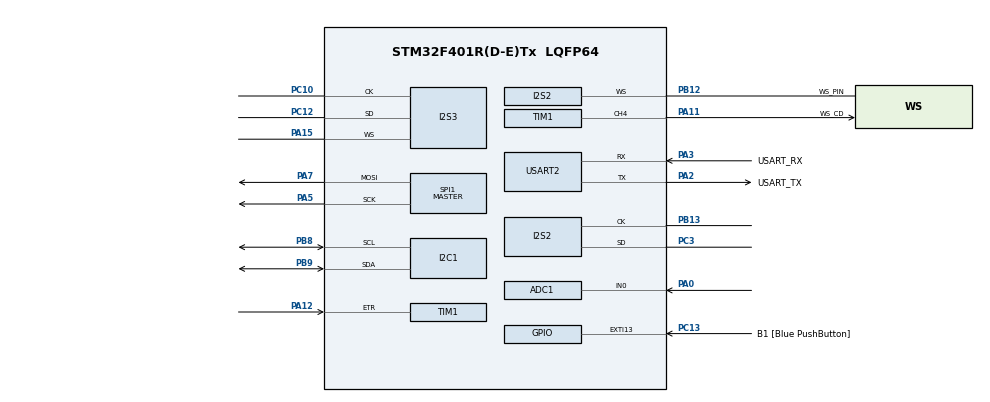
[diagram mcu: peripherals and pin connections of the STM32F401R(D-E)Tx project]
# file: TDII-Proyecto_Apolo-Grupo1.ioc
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ADC1.Channel-0\#ChannelRegularConversion=ADC_CHANNEL_0
ADC1.NbrOfConversionFlag=1
ADC1.Rank-0\#ChannelRegularConversion=1
ADC1.Resolution=ADC_RESOLUTION_10B
ADC1.SamplingTime-0\#ChannelRegularConversion=ADC_SAMPLETIME_3CYCLES
ADC1.master=1
Dma.Request0=SPI3_TX
Dma.Request1=SPI2_RX
Dma.Request2=SPI1_TX
Dma.SPI1_TX.2.Direction=DMA_MEMORY_TO_PERIPH
Dma.SPI1_TX.2.FIFOMode=DMA_FIFOMODE_DISABLE
Dma.SPI1_TX.2.Instance=DMA2_Stream3
Dma.SPI1_TX.2.MemDataAlignment=DMA_MDATAALIGN_BYTE
Dma.SPI1_TX.2.MemInc=DMA_MINC_ENABLE
Dma.SPI1_TX.2.Mode=DMA_CIRCULAR
Dma.SPI1_TX.2.PeriphDataAlignment=DMA_PDATAALIGN_BYTE
Dma.SPI1_TX.2.PeriphInc=DMA_PINC_DISABLE
Dma.SPI1_TX.2.Priority=DMA_PRIORITY_VERY_HIGH
Dma.SPI2_RX.1.Direction=DMA_PERIPH_TO_MEMORY
Dma.SPI2_RX.1.FIFOMode=DMA_FIFOMODE_DISABLE
Dma.SPI2_RX.1.Instance=DMA1_Stream3
Dma.SPI2_RX.1.MemDataAlignment=DMA_MDATAALIGN_HALFWORD
Dma.SPI2_RX.1.MemInc=DMA_MINC_ENABLE
Dma.SPI2_RX.1.Mode=DMA_CIRCULAR
Dma.SPI2_RX.1.PeriphDataAlignment=DMA_PDATAALIGN_HALFWORD
Dma.SPI2_RX.1.PeriphInc=DMA_PINC_DISABLE
Dma.SPI2_RX.1.Priority=DMA_PRIORITY_VERY_HIGH
Dma.SPI3_TX.0.Direction=DMA_MEMORY_TO_PERIPH
Dma.SPI3_TX.0.FIFOMode=DMA_FIFOMODE_DISABLE
Dma.SPI3_TX.0.Instance=DMA1_Stream5
Dma.SPI3_TX.0.MemDataAlignment=DMA_MDATAALIGN_HALFWORD
Dma.SPI3_TX.0.MemInc=DMA_MINC_ENABLE
Dma.SPI3_TX.0.Mode=DMA_CIRCULAR
Dma.SPI3_TX.0.PeriphDataAlignment=DMA_PDATAALIGN_HALFWORD
Dma.SPI3_TX.0.PeriphInc=DMA_PINC_DISABLE
Dma.SPI3_TX.0.Priority=DMA_PRIORITY_VERY_HIGH
FREERTOS.Tasks01=defaultTask,0,128,StartDefaultTask,Default,NULL,Dynamic,NULL,NULL
FREERTOS.configENABLE_FPU=1
FREERTOS.configTOTAL_HEAP_SIZE=30000
FREERTOS.configUSE_NEWLIB_REENTRANT=1
I2S2.AudioFreq=AudioFreqCustomValue
I2S2.AudioFreqCustom=44100
I2S2.CPOL=I2S_CPOL_HIGH
I2S2.ErrorAudioFreq=0.26 %
I2S2.FullDuplexMode=I2S_FULLDUPLEXMODE_DISABLE
I2S2.Instance=SPI$Index
I2S2.Mode=I2S_MODE_SLAVE_RX
I2S2.RealAudioFreq=44.117 KHz
I2S2.VirtualMode=I2S_MODE_SLAVE
I2S3.AudioFreq=AudioFreqCustomValue
I2S3.AudioFreqCustom=44100
I2S3.CPOL=I2S_CPOL_HIGH
I2S3.ErrorAudioFreq=0.26 %
I2S3.FullDuplexMode=I2S_FULLDUPLEXMODE_DISABLE
I2S3.Instance=SPI$Index
I2S3.RealAudioFreq=44.117 KHz
I2S3.VirtualMode=I2S_MODE_MASTER
Mcu.Family=STM32F4
Mcu.Name=STM32F401R(D-E)Tx
Mcu.Package=LQFP64
NVIC.DMA1_Stream3_IRQn=true\:5\:0\:false\:false\:true\:true\:false\:true\:true
NVIC.DMA1_Stream5_IRQn=true\:5\:0\:false\:false\:true\:true\:false\:true\:true
NVIC.DMA2_Stream3_IRQn=true\:5\:0\:false\:false\:true\:true\:false\:true\:true
NVIC.PriorityGroup=NVIC_PRIORITYGROUP_4
NVIC.TIM3_IRQn=true\:15\:0\:false\:false\:true\:false\:false\:true\:true
NVIC.TimeBase=TIM3_IRQn
NVIC.TimeBaseIP=TIM3
PA0-WKUP.Signal=ADCx_IN0
PA11.GPIO_Label=WS_CD
PA11.GPIO_Speed=GPIO_SPEED_FREQ_VERY_HIGH
PA11.Signal=S_TIM1_CH4
PA12.Signal=S_TIM1_ETR
PA13.GPIO_Label=TMS
PA13.Mode=Serial_Wire
PA13.Signal=SYS_JTMS-SWDIO
PA14.GPIO_Label=TCK
PA14.Mode=Serial_Wire
PA14.Signal=SYS_JTCK-SWCLK
PA15.GPIO_Speed=GPIO_SPEED_FREQ_HIGH
PA15.Mode=Half_Duplex_Master
PA15.Signal=I2S3_WS
PA2.GPIO_Label=USART_TX
PA2.GPIO_Mode=GPIO_MODE_AF_PP
PA2.GPIO_PuPd=GPIO_NOPULL
PA2.GPIO_Speed=GPIO_SPEED_FREQ_LOW
PA2.Mode=Asynchronous
PA2.Signal=USART2_TX
PA3.GPIO_Label=USART_RX
PA3.GPIO_Mode=GPIO_MODE_AF_PP
PA3.GPIO_PuPd=GPIO_NOPULL
PA3.GPIO_Speed=GPIO_SPEED_FREQ_LOW
PA3.Mode=Asynchronous
PA3.Signal=USART2_RX
PA5.Mode=TX_Only_Simplex_Unidirect_Master
PA5.Signal=SPI1_SCK
PA7.Mode=TX_Only_Simplex_Unidirect_Master
PA7.Signal=SPI1_MOSI
PB12.GPIO_Label=WS_PIN
PB12.GPIO_Speed=GPIO_SPEED_FREQ_HIGH
PB12.Mode=Half_Duplex_Slave
PB12.Signal=I2S2_WS
PB13.GPIO_Speed=GPIO_SPEED_FREQ_HIGH
PB13.Mode=Half_Duplex_Slave
PB13.Signal=I2S2_CK
PB8.GPIO_Pu=GPIO_PULLUP
PB8.Mode=I2C
PB8.Signal=I2C1_SCL
PB9.GPIO_Pu=GPIO_PULLUP
PB9.Mode=I2C
PB9.Signal=I2C1_SDA
PC10.GPIO_Speed=GPIO_SPEED_FREQ_HIGH
PC10.Mode=Half_Duplex_Master
PC10.Signal=I2S3_CK
PC12.GPIO_Speed=GPIO_SPEED_FREQ_HIGH
PC12.Mode=Half_Duplex_Master
PC12.Signal=I2S3_SD
PC13-ANTI_TAMP.GPIO_Label=B1 [Blue PushButton]
PC13-ANTI_TAMP.GPIO_ModeDefaultEXTI=GPIO_MODE_IT_FALLING
PC13-ANTI_TAMP.GPIO_PuPd=GPIO_NOPULL
PC13-ANTI_TAMP.Signal=GPXTI13
PC14-OSC32_IN.Mode=LSE-External-Oscillator
PC14-OSC32_IN.Signal=RCC_OSC32_IN
PC15-OSC32_OUT.Mode=LSE-External-Oscillator
PC15-OSC32_OUT.Signal=RCC_OSC32_OUT
PC3.GPIO_Speed=GPIO_SPEED_FREQ_HIGH
PC3.Mode=Half_Duplex_Slave
PC3.Signal=I2S2_SD
PH0\ -\ OSC_IN.Mode=HSE-External-Clock-Source
PH0\ -\ OSC_IN.Signal=RCC_OSC_IN
PH1\ -\ OSC_OUT.Mode=HSE-External-Clock-Source
PH1\ -\ OSC_OUT.Signal=RCC_OSC_OUT
ProjectManager.HeapSize=0x200
ProjectManager.StackSize=0x400
ProjectManager.TargetToolchain=STM32CubeIDE
RCC.48MHZClocksFreq_Value=19428571.42857143
RCC.AHBFreq_Value=68000000
RCC.APB1CLKDivider=RCC_HCLK_DIV2
RCC.APB1Freq_Value=34000000
RCC.APB1TimFreq_Value=68000000
RCC.APB2Freq_Value=68000000
RCC.APB2TimFreq_Value=68000000
RCC.CortexFreq_Value=68000000
RCC.HCLKFreq_Value=68000000
RCC.HSE_VALUE=8000000
RCC.HSI_VALUE=16000000
RCC.PLLI2SN=72
RCC.PLLI2SR=3
RCC.PLLM=4
RCC.PLLN=68
RCC.PLLQ=7
RCC.PLLSourceVirtual=RCC_PLLSOURCE_HSE
RCC.SYSCLKFreq_VALUE=68000000
RCC.SYSCLKSource=RCC_SYSCLKSOURCE_PLLCLK
RCC.VCOOutputFreq_Value=136000000
SH.ADCx_IN0.0=ADC1_IN0,IN0
SH.S_TIM1_CH4.0=TIM1_CH4,Output Compare4 CH4
SH.S_TIM1_ETR.0=TIM1_ETR,ClockSourceETR_Mode2
SPI1.BaudRatePrescaler=SPI_BAUDRATEPRESCALER_32
SPI1.DataSize=SPI_DATASIZE_8BIT
SPI1.Direction=SPI_DIRECTION_2LINES
SPI1.Mode=SPI_MODE_MASTER
SPI1.VirtualType=VM_MASTER
STMicroelectronics.X-CUBE-TOUCHGFX.4.22.0.ApplicationCcGraphicsJjApplication=TouchGFXOoGenerator
STMicroelectronics.X-CUBE-TOUCHGFX.4.22.0.tgfx_buffering_strategy=Partial
STMicroelectronics.X-CUBE-TOUCHGFX.4.22.0.tgfx_custom_height=320
STMicroelectronics.X-CUBE-TOUCHGFX.4.22.0.tgfx_custom_width=480
STMicroelectronics.X-CUBE-TOUCHGFX.4.22.0_IsPackSelfContextualization=true
TIM1.Channel-Output\ Compare4\ CH4=TIM_CHANNEL_4
TIM1.OC4Preload=DISABLE
TIM1.OCMode_4=TIM_OCMODE_TOGGLE
TIM1.Period=23
TIM1.Pulse-Output\ Compare4\ CH4=0
TIM2.Prescaler=0
USART2.VirtualMode=VM_ASYNC
VP_CRC_VS_CRC.Mode=CRC_Activate
VP_FREERTOS_VS_CMSIS_V1.Mode=CMSIS_V1
VP_STMicroelectronics.X-CUBE-TOUCHGFX_VS_GraphicsJjApplication_4.22.0.Mode=GraphicsJjApplication
VP_SYS_VS_tim3.Mode=TIM3
VP_TIM2_VS_ClockSourceINT.Mode=Internal
board=NUCLEO-F401RE

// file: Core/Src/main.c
/* USER CODE BEGIN Header */
/**
  ******************************************************************************
  * @file           : main.c
  * @brief          : Main program body
  ******************************************************************************
  * @attention
  *
  * Copyright (c) 2023 STMicroelectronics.
  * All rights reserved.
  *
  * This software is licensed under terms that can be found in the LICENSE file
  * in the root directory of this software component.
  * If no LICENSE file comes with this software, it is provided AS-IS.
  *
  ******************************************************************************
  */
/* USER CODE END Header */
#include "main.h"
#include "cmsis_os.h"
#include "app_touchgfx.h"

/* USER CODE BEGIN PTD */
#include "Driver_I2S.h"
#include "process.h"
/* USER CODE END PTD */

ADC_HandleTypeDef hadc1;

CRC_HandleTypeDef hcrc;

I2C_HandleTypeDef hi2c1;

I2S_HandleTypeDef hi2s2;
I2S_HandleTypeDef hi2s3;
DMA_HandleTypeDef hdma_spi2_rx;
DMA_HandleTypeDef hdma_spi3_tx;

SPI_HandleTypeDef hspi1;
DMA_HandleTypeDef hdma_spi1_tx;

TIM_HandleTypeDef htim1;
TIM_HandleTypeDef htim2;

UART_HandleTypeDef huart2;

osThreadId defaultTaskHandle;
/* USER CODE BEGIN PV */
SemaphoreHandle_t semSaveData;
SemaphoreHandle_t semProcessData; // semaforo para indicar si se puede tocar o no el buffer de entrada/salida
SemaphoreHandle_t semCalcCoefs;
SemaphoreHandle_t semI2CResource;
SemaphoreHandle_t semCalcVolume;
SemaphoreHandle_t semDataReady;

/* USER CODE END PV */

void SystemClock_Config(void);
void PeriphCommonClock_Config(void);
static void MX_GPIO_Init(void);
static void MX_DMA_Init(void);
static void MX_USART2_UART_Init(void);
static void MX_ADC1_Init(void);
static void MX_CRC_Init(void);
static void MX_TIM2_Init(void);
static void MX_I2C1_Init(void);
static void MX_I2S3_Init(void);
static void MX_TIM1_Init(void);
static void MX_I2S2_Init(void);
static void MX_SPI1_Init(void);
void StartDefaultTask(void const * argument);

/* USER CODE BEGIN 0 */

/*
uint32_t tim1_cuenta=0;
extern TIM_HandleTypeDef htim2;
extern uint32_t tim1_cuenta;
tim1_cuenta = 0 ;
__HAL_TIM_SET_COUNTER(&htim2,0);
tim1_cuenta = __HAL_TIM_GET_COUNTER(&htim2);
*/

//I2S 2
void HAL_I2S_RxCpltCallback(I2S_HandleTypeDef *hi2s) {
	callbackI2SRx_CMP();
}
void HAL_I2S_RxHalfCpltCallback(I2S_HandleTypeDef *hi2s) {
	callbackI2SRx_HALF();
}

//I2S 3
void HAL_I2S_TxCpltCallback(I2S_HandleTypeDef *hi2s) {
	callbackI2STx_CMP();
}
void HAL_I2S_TxHalfCpltCallback(I2S_HandleTypeDef *hi2s) {
	callbackI2STx_HALF();
}
void HAL_SPI_TxCpltCallback(SPI_HandleTypeDef *hspi) {
	callbackSPITx_CMP();
}
void HAL_SPI_TxHalfCallback(SPI_HandleTypeDef *hspi) {
	callbackSPITx_HALF();
}

void HAL_TIM_TriggerCallback(TIM_HandleTypeDef *htim){

}
/* USER CODE END 0 */

int main(void)
{

  /* MCU Configuration--------------------------------------------------------*/

  /* Reset of all peripherals, Initializes the Flash interface and the Systick. */
  HAL_Init();

  /* Configure the system clock */
  SystemClock_Config();

/* Configure the peripherals common clocks */
  PeriphCommonClock_Config();

  /* Initialize all configured peripherals */
  MX_GPIO_Init();
  MX_DMA_Init();
  MX_USART2_UART_Init();
  MX_ADC1_Init();
  MX_CRC_Init();
  MX_TIM2_Init();
  MX_I2C1_Init();
  MX_I2S3_Init();
  MX_TIM1_Init();
  MX_I2S2_Init();
  MX_SPI1_Init();
  MX_TouchGFX_Init();
  /* Call PreOsInit function */
  MX_TouchGFX_PreOSInit();
  /* USER CODE BEGIN 2 */
  HAL_TIM_Base_Start(&htim2); // lo uso para medir tiempos

  /* USER CODE END 2 */

  /* USER CODE BEGIN RTOS_SEMAPHORES */
  /* add semaphores, ... */
  init_semaphores();

  /* USER CODE END RTOS_SEMAPHORES */

  /* USER CODE BEGIN RTOS_QUEUES */
  /* add queues, ... */
#if 0
  /* USER CODE END RTOS_QUEUES */

  /* Create the thread(s) */
  /* definition and creation of defaultTask */
  osThreadDef(defaultTask, StartDefaultTask, osPriorityNormal, 0, 128);
  defaultTaskHandle = osThreadCreate(osThread(defaultTask), NULL);

  /* USER CODE BEGIN RTOS_THREADS */
#endif

  init_tasks();

  /* add threads, ... */
  vTaskStartScheduler();
  /* USER CODE END RTOS_THREADS */

  /* Start scheduler */
  osKernelStart();

  /* We should never get here as control is now taken by the scheduler */
  /* Infinite loop */
  while (1)
  {

  }
}

void SystemClock_Config(void)
{
  RCC_OscInitTypeDef RCC_OscInitStruct = {0};
  RCC_ClkInitTypeDef RCC_ClkInitStruct = {0};

  /** Configure the main internal regulator output voltage
  */
  __HAL_RCC_PWR_CLK_ENABLE();
  __HAL_PWR_VOLTAGESCALING_CONFIG(PWR_REGULATOR_VOLTAGE_SCALE2);

  /** Initializes the RCC Oscillators according to the specified parameters
  * in the RCC_OscInitTypeDef structure.
  */
  RCC_OscInitStruct.OscillatorType = RCC_OSCILLATORTYPE_HSE;
  RCC_OscInitStruct.HSEState = RCC_HSE_BYPASS;
  RCC_OscInitStruct.PLL.PLLState = RCC_PLL_ON;
  RCC_OscInitStruct.PLL.PLLSource = RCC_PLLSOURCE_HSE;
  RCC_OscInitStruct.PLL.PLLM = 4;
  RCC_OscInitStruct.PLL.PLLN = 84;
  RCC_OscInitStruct.PLL.PLLP = RCC_PLLP_DIV2;
  RCC_OscInitStruct.PLL.PLLQ = 7;
  if (HAL_RCC_OscConfig(&RCC_OscInitStruct) != HAL_OK)
  {
    Error_Handler();
  }

  /** Initializes the CPU, AHB and APB buses clocks
  */
  RCC_ClkInitStruct.ClockType = RCC_CLOCKTYPE_HCLK|RCC_CLOCKTYPE_SYSCLK
                              |RCC_CLOCKTYPE_PCLK1|RCC_CLOCKTYPE_PCLK2;
  RCC_ClkInitStruct.SYSCLKSource = RCC_SYSCLKSOURCE_PLLCLK;
  RCC_ClkInitStruct.AHBCLKDivider = RCC_SYSCLK_DIV1;
  RCC_ClkInitStruct.APB1CLKDivider = RCC_HCLK_DIV2;
  RCC_ClkInitStruct.APB2CLKDivider = RCC_HCLK_DIV1;

  if (HAL_RCC_ClockConfig(&RCC_ClkInitStruct, FLASH_LATENCY_2) != HAL_OK)
  {
    Error_Handler();
  }
}

void PeriphCommonClock_Config(void)
{
  RCC_PeriphCLKInitTypeDef PeriphClkInitStruct = {0};

  /** Initializes the peripherals clock
  */
  PeriphClkInitStruct.PeriphClockSelection = RCC_PERIPHCLK_I2S;
  PeriphClkInitStruct.PLLI2S.PLLI2SN = 72;
  PeriphClkInitStruct.PLLI2S.PLLI2SR = 3;
  if (HAL_RCCEx_PeriphCLKConfig(&PeriphClkInitStruct) != HAL_OK)
  {
    Error_Handler();
  }
}

static void MX_ADC1_Init(void)
{

  ADC_ChannelConfTypeDef sConfig = {0};

  /** Configure the global features of the ADC (Clock, Resolution, Data Alignment and number of conversion)
  */
  hadc1.Instance = ADC1;
  hadc1.Init.ClockPrescaler = ADC_CLOCK_SYNC_PCLK_DIV4;
  hadc1.Init.Resolution = ADC_RESOLUTION_10B;
  hadc1.Init.ScanConvMode = DISABLE;
  hadc1.Init.ContinuousConvMode = DISABLE;
  hadc1.Init.DiscontinuousConvMode = DISABLE;
  hadc1.Init.ExternalTrigConvEdge = ADC_EXTERNALTRIGCONVEDGE_NONE;
  hadc1.Init.ExternalTrigConv = ADC_SOFTWARE_START;
  hadc1.Init.DataAlign = ADC_DATAALIGN_RIGHT;
  hadc1.Init.NbrOfConversion = 1;
  hadc1.Init.DMAContinuousRequests = DISABLE;
  hadc1.Init.EOCSelection = ADC_EOC_SINGLE_CONV;
  if (HAL_ADC_Init(&hadc1) != HAL_OK)
  {
    Error_Handler();
  }

  /** Configure for the selected ADC regular channel its corresponding rank in the sequencer and its sample time.
  */
  sConfig.Channel = ADC_CHANNEL_0;
  sConfig.Rank = 1;
  sConfig.SamplingTime = ADC_SAMPLETIME_3CYCLES;
  if (HAL_ADC_ConfigChannel(&hadc1, &sConfig) != HAL_OK)
  {
    Error_Handler();
  }

}

static void MX_CRC_Init(void)
{

  hcrc.Instance = CRC;
  if (HAL_CRC_Init(&hcrc) != HAL_OK)
  {
    Error_Handler();
  }

}

static void MX_I2C1_Init(void)
{

  hi2c1.Instance = I2C1;
  hi2c1.Init.ClockSpeed = 100000;
  hi2c1.Init.DutyCycle = I2C_DUTYCYCLE_2;
  hi2c1.Init.OwnAddress1 = 0;
  hi2c1.Init.AddressingMode = I2C_ADDRESSINGMODE_7BIT;
  hi2c1.Init.DualAddressMode = I2C_DUALADDRESS_DISABLE;
  hi2c1.Init.OwnAddress2 = 0;
  hi2c1.Init.GeneralCallMode = I2C_GENERALCALL_DISABLE;
  hi2c1.Init.NoStretchMode = I2C_NOSTRETCH_DISABLE;
  if (HAL_I2C_Init(&hi2c1) != HAL_OK)
  {
    Error_Handler();
  }

}

static void MX_I2S2_Init(void)
{

  hi2s2.Instance = SPI2;
  hi2s2.Init.Mode = I2S_MODE_SLAVE_RX;
  hi2s2.Init.Standard = I2S_STANDARD_PHILIPS;
  hi2s2.Init.DataFormat = I2S_DATAFORMAT_16B;
  hi2s2.Init.MCLKOutput = I2S_MCLKOUTPUT_DISABLE;
  hi2s2.Init.AudioFreq = 44100;
  hi2s2.Init.CPOL = I2S_CPOL_HIGH;
  hi2s2.Init.ClockSource = I2S_CLOCK_PLL;
  hi2s2.Init.FullDuplexMode = I2S_FULLDUPLEXMODE_DISABLE;
  if (HAL_I2S_Init(&hi2s2) != HAL_OK)
  {
    Error_Handler();
  }

}

static void MX_I2S3_Init(void)
{

  hi2s3.Instance = SPI3;
  hi2s3.Init.Mode = I2S_MODE_MASTER_TX;
  hi2s3.Init.Standard = I2S_STANDARD_PHILIPS;
  hi2s3.Init.DataFormat = I2S_DATAFORMAT_16B;
  hi2s3.Init.MCLKOutput = I2S_MCLKOUTPUT_DISABLE;
  hi2s3.Init.AudioFreq = 44100;
  hi2s3.Init.CPOL = I2S_CPOL_HIGH;
  hi2s3.Init.ClockSource = I2S_CLOCK_PLL;
  hi2s3.Init.FullDuplexMode = I2S_FULLDUPLEXMODE_DISABLE;
  if (HAL_I2S_Init(&hi2s3) != HAL_OK)
  {
    Error_Handler();
  }

}

static void MX_SPI1_Init(void)
{

  /* SPI1 parameter configuration*/
  hspi1.Instance = SPI1;
  hspi1.Init.Mode = SPI_MODE_MASTER;
  hspi1.Init.Direction = SPI_DIRECTION_2LINES;
  hspi1.Init.DataSize = SPI_DATASIZE_16BIT;
  hspi1.Init.CLKPolarity = SPI_POLARITY_LOW;
  hspi1.Init.CLKPhase = SPI_PHASE_1EDGE;
  hspi1.Init.NSS = SPI_NSS_SOFT;
  hspi1.Init.BaudRatePrescaler = SPI_BAUDRATEPRESCALER_64;
  hspi1.Init.FirstBit = SPI_FIRSTBIT_MSB;
  hspi1.Init.TIMode = SPI_TIMODE_DISABLE;
  hspi1.Init.CRCCalculation = SPI_CRCCALCULATION_DISABLE;
  hspi1.Init.CRCPolynomial = 10;
  if (HAL_SPI_Init(&hspi1) != HAL_OK)
  {
    Error_Handler();
  }

}

static void MX_TIM1_Init(void)
{

  TIM_ClockConfigTypeDef sClockSourceConfig = {0};
  TIM_MasterConfigTypeDef sMasterConfig = {0};
  TIM_OC_InitTypeDef sConfigOC = {0};
  TIM_BreakDeadTimeConfigTypeDef sBreakDeadTimeConfig = {0};

  htim1.Instance = TIM1;
  htim1.Init.Prescaler = 0;
  htim1.Init.CounterMode = TIM_COUNTERMODE_UP;
  htim1.Init.Period = 15;
  htim1.Init.ClockDivision = TIM_CLOCKDIVISION_DIV1;
  htim1.Init.RepetitionCounter = 0;
  htim1.Init.AutoReloadPreload = TIM_AUTORELOAD_PRELOAD_DISABLE;
  if (HAL_TIM_Base_Init(&htim1) != HAL_OK)
  {
    Error_Handler();
  }
  sClockSourceConfig.ClockSource = TIM_CLOCKSOURCE_ETRMODE2;
  sClockSourceConfig.ClockPolarity = TIM_CLOCKPOLARITY_NONINVERTED;
  sClockSourceConfig.ClockPrescaler = TIM_CLOCKPRESCALER_DIV1;
  sClockSourceConfig.ClockFilter = 0;
  if (HAL_TIM_ConfigClockSource(&htim1, &sClockSourceConfig) != HAL_OK)
  {
    Error_Handler();
  }
  if (HAL_TIM_OC_Init(&htim1) != HAL_OK)
  {
    Error_Handler();
  }
  sMasterConfig.MasterOutputTrigger = TIM_TRGO_RESET;
  sMasterConfig.MasterSlaveMode = TIM_MASTERSLAVEMODE_DISABLE;
  if (HAL_TIMEx_MasterConfigSynchronization(&htim1, &sMasterConfig) != HAL_OK)
  {
    Error_Handler();
  }
  sConfigOC.OCMode = TIM_OCMODE_TOGGLE;
  sConfigOC.Pulse = 0;
  sConfigOC.OCPolarity = TIM_OCPOLARITY_HIGH;
  sConfigOC.OCFastMode = TIM_OCFAST_DISABLE;
  sConfigOC.OCIdleState = TIM_OCIDLESTATE_RESET;
  sConfigOC.OCNIdleState = TIM_OCNIDLESTATE_RESET;
  if (HAL_TIM_OC_ConfigChannel(&htim1, &sConfigOC, TIM_CHANNEL_4) != HAL_OK)
  {
    Error_Handler();
  }
  sBreakDeadTimeConfig.OffStateRunMode = TIM_OSSR_DISABLE;
  sBreakDeadTimeConfig.OffStateIDLEMode = TIM_OSSI_DISABLE;
  sBreakDeadTimeConfig.LockLevel = TIM_LOCKLEVEL_OFF;
  sBreakDeadTimeConfig.DeadTime = 0;
  sBreakDeadTimeConfig.BreakState = TIM_BREAK_DISABLE;
  sBreakDeadTimeConfig.BreakPolarity = TIM_BREAKPOLARITY_HIGH;
  sBreakDeadTimeConfig.AutomaticOutput = TIM_AUTOMATICOUTPUT_DISABLE;
  if (HAL_TIMEx_ConfigBreakDeadTime(&htim1, &sBreakDeadTimeConfig) != HAL_OK)
  {
    Error_Handler();
  }
  HAL_TIM_MspPostInit(&htim1);

}

static void MX_TIM2_Init(void)
{

  TIM_ClockConfigTypeDef sClockSourceConfig = {0};
  TIM_MasterConfigTypeDef sMasterConfig = {0};

  htim2.Instance = TIM2;
  htim2.Init.Prescaler = 0;
  htim2.Init.CounterMode = TIM_COUNTERMODE_UP;
  htim2.Init.Period = 4294967295;
  htim2.Init.ClockDivision = TIM_CLOCKDIVISION_DIV1;
  htim2.Init.AutoReloadPreload = TIM_AUTORELOAD_PRELOAD_DISABLE;
  if (HAL_TIM_Base_Init(&htim2) != HAL_OK)
  {
    Error_Handler();
  }
  sClockSourceConfig.ClockSource = TIM_CLOCKSOURCE_INTERNAL;
  if (HAL_TIM_ConfigClockSource(&htim2, &sClockSourceConfig) != HAL_OK)
  {
    Error_Handler();
  }
  sMasterConfig.MasterOutputTrigger = TIM_TRGO_RESET;
  sMasterConfig.MasterSlaveMode = TIM_MASTERSLAVEMODE_DISABLE;
  if (HAL_TIMEx_MasterConfigSynchronization(&htim2, &sMasterConfig) != HAL_OK)
  {
    Error_Handler();
  }

}

static void MX_USART2_UART_Init(void)
{

  huart2.Instance = USART2;
  huart2.Init.BaudRate = 115200;
  huart2.Init.WordLength = UART_WORDLENGTH_8B;
  huart2.Init.StopBits = UART_STOPBITS_1;
  huart2.Init.Parity = UART_PARITY_NONE;
  huart2.Init.Mode = UART_MODE_TX_RX;
  huart2.Init.HwFlowCtl = UART_HWCONTROL_NONE;
  huart2.Init.OverSampling = UART_OVERSAMPLING_16;
  if (HAL_UART_Init(&huart2) != HAL_OK)
  {
    Error_Handler();
  }

}

static void MX_DMA_Init(void)
{

  /* DMA controller clock enable */
  __HAL_RCC_DMA1_CLK_ENABLE();
  __HAL_RCC_DMA2_CLK_ENABLE();

  /* DMA interrupt init */
  /* DMA1_Stream3_IRQn interrupt configuration */
  HAL_NVIC_SetPriority(DMA1_Stream3_IRQn, 5, 0);
  HAL_NVIC_EnableIRQ(DMA1_Stream3_IRQn);
  /* DMA1_Stream5_IRQn interrupt configuration */
  HAL_NVIC_SetPriority(DMA1_Stream5_IRQn, 5, 0);
  HAL_NVIC_EnableIRQ(DMA1_Stream5_IRQn);
  /* DMA2_Stream3_IRQn interrupt configuration */
  HAL_NVIC_SetPriority(DMA2_Stream3_IRQn, 5, 0);
  HAL_NVIC_EnableIRQ(DMA2_Stream3_IRQn);

}

static void MX_GPIO_Init(void)
{
  GPIO_InitTypeDef GPIO_InitStruct = {0};

  /* GPIO Ports Clock Enable */
  __HAL_RCC_GPIOC_CLK_ENABLE();
  __HAL_RCC_GPIOH_CLK_ENABLE();
  __HAL_RCC_GPIOA_CLK_ENABLE();
  __HAL_RCC_GPIOB_CLK_ENABLE();

  /*Configure GPIO pin : B1_Pin */
  GPIO_InitStruct.Pin = B1_Pin;
  GPIO_InitStruct.Mode = GPIO_MODE_IT_FALLING;
  GPIO_InitStruct.Pull = GPIO_NOPULL;
  HAL_GPIO_Init(B1_GPIO_Port, &GPIO_InitStruct);

}

void StartDefaultTask(void const * argument)
{
  for(;;)
  {
    osDelay(1);
  }
}

void HAL_TIM_PeriodElapsedCallback(TIM_HandleTypeDef *htim)
{
  if (htim->Instance == TIM3) {
    HAL_IncTick();
  }
}

void Error_Handler(void)
{
  __disable_irq();
  while (1)
  {
  }
}
